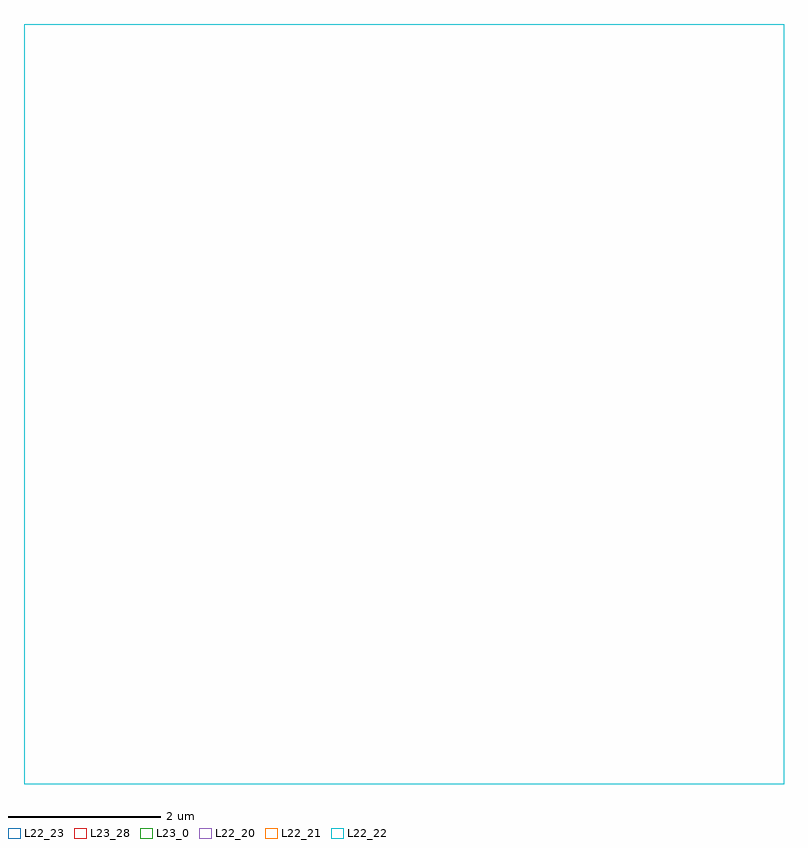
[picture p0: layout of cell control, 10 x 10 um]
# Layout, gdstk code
import gdstk
lib = gdstk.Library(unit=1e-6, precision=1e-09)
def R(c, l, rs):  # rectangles x0, y0, x1, y1
    for r in rs: c.add(gdstk.rectangle(r[:2], r[2:], *l))
L22_20 = (22, 20)
L22_21 = (22, 21)
L22_22 = (22, 22)
L22_23 = (22, 23)
L23_0 = (23, 0)
L23_28 = (23, 28)

control = lib.new_cell('control')
R(control, L22_20, [(0,0,10,10)])
R(control, L22_21, [(0,0,10,10)])
R(control, L22_22, [(0,0,10,10)])
R(control, L22_23, [(0,0,10,10)])
R(control, L23_0, [(0,0,10,10)])
R(control, L23_28, [(0,0,10,10)])

lib.write_gds('control.gds')
